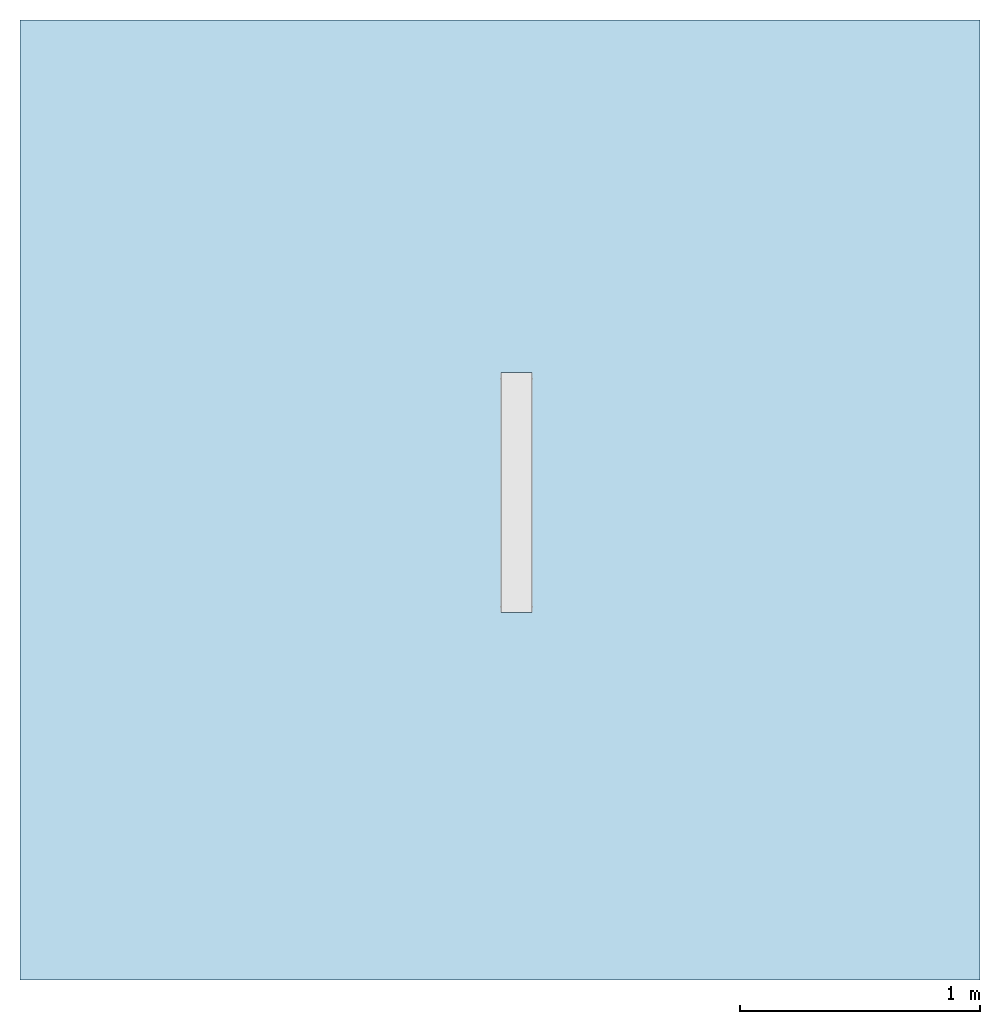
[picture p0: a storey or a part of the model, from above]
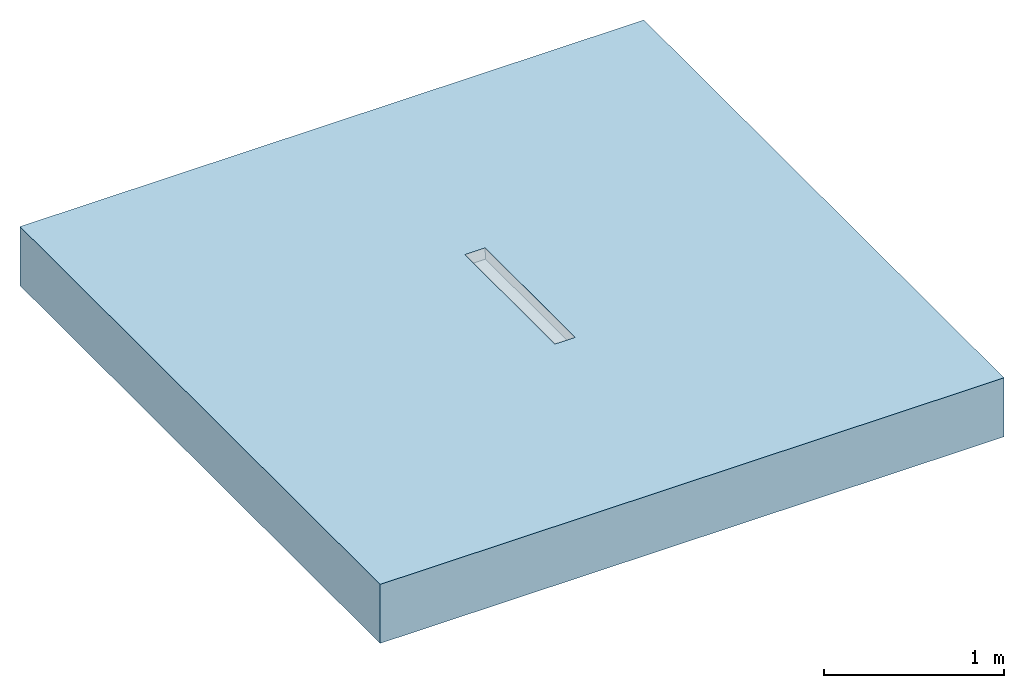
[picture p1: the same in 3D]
Properties of the parts of a building model (IFC2X3)

# File
Description: ViewDefinition [CoordinationView]
File name: Project Number
Time: 2014-06-06T14:47:46
Written by: The EXPRESS Data Manager Version 5.01.0100.02.64mod : 6 Jun 2012
Made in: 20130308_1515(x64) - Exporter 2014.0.2013.0308 - Default UI
Comment: STEP Physical File produced by: The EXPRESS Data Manager Version 5.01.0100.02.64mod : 6 Jun 2012 * Module: EDMstepFileFactory/EDMstandAlone * Creation date: Fri Jun 06 14:47:46 2014 * Host: IN-BLR-PC-0010 * Database: C:\Users\palleri\AppData\Local\Temp\{3695704A-249B-45A1-9260-636B70878DE3}\ifc * Database version: 5507 * Database creation date: Fri Jun 06 14:47:45 2014 * Schema: IFC2X3 * Model: DataRepository.ifc * Model creation date: Fri Jun 06 14:47:45 2014 * Header model: DataRepository.ifc_HeaderModel * Header model creation date: Fri Jun 06 14:47:45 2014 * EDMuser: sdai-user * EDMgroup: sdai-group * License ID and type: 5605 : Permanent license. Expiry date: * EDMstepFileFactory options: 020000

# IfcProject, Project Number
LongName: Project Name; Phase: Project Status

# IfcSite, Default
RefLatitude: 42, 21, 30, 344238; RefLongitude: -71, -3, -35, -194702; RefElevation: 0 mm

# IfcBuilding
Pset_BuildingCommon - NumberOfStoreys: 1
Other - Project Status: Project Status; Client Name: Owner; Project Address: ## Street City, State Zip; Project Name: Project Name; Project Issue Date: Issue Date; Project Number: Project Number

# IfcBuildingStorey, Level 1
LongName: Level 1; Elevation: 0 mm
Constraints - Elevation Base: Project Base Point; Elevation: 0 mm
Graphics - Symbol at End 1 Default: no; Line Weight: 1; Symbol: M_Level Head - Circle: M_Level Head - Circle; Symbol at End 2 Default: yes; Color: 0; Line Pattern: Center
Identity Data - Building Story: yes; Structural: no; Name: Level 1
Dimensions - Computation Height: 0 mm

# IfcFlowTerminal: 36943 - Adjustable Channel - Shallow Section - 1000mm LG - Invert Depth 55/77mm, ACO Freedeck Adjustable Height Channel Shallow Section Stainless Steel:36943 - Adjustable Channel - Shallow Section - 1000mm LG - Invert Depth 55/77mm:317948
In: Level 1
Material: Stainless Steel Grade 304
Dimensions - Height @ Invert 1 (55 -77mm): 77 mm; Height @ Invert 2 (55 -77mm): 77 mm; Channel End Length: -1000 mm; Grating End Length: 1000 mm
Other - Height @ Invert 2 Min & Max: 77 mm; Height @ Invert 1 Min & Max: 77 mm; Top Piece Void Height @ Invert 1: 31 mm; Top Piece Void Height @ Invert 2: 31 mm; Nos: 32
Construction - End Plate Invert 2: no; 36954 - Grating - Plain Mesh - Stainless Steel 304 - 500mm long: no; End Plate Invert 1: no; 00272 - Grating - Slotted Grating - Stainless Steel 304 - 1000mm long: no; 36955 - Grating - Plain Mesh - Stainless Steel 304 - 1000mm long: yes; 00273 - Grating - Slotted Grating - Stainless Steel 304 - 500mm long: no
Phasing - Phase Created: New Construction
Constraints - Moves With Nearby Elements: no; Level: Level: Level 1
Identity Data - Mark: 29; E-mail Sales: abdcommercial@aco.co.uk; Watermarked With: BIM Manager Premium Suite; Watermarked By: www.acobd.com; Watermark1: This file is the property of ACO Technologies PLC; Watermark2: This file is water marked and users are prohibited to reproduce, adapt, distribute this information; E-mail Technical: abdtechnical@aco.co.uk; Website: www.acobd.com; Address: ACO Business Centre, Caxton Road, Bedford, MK41 0LF; Fax: +44 (0)1462 851490; Manufacturer: ACO Building Drainage; Telephone: +44 (0)1462 816666
Pset_ManufacturerTypeInformation - Manufacturer: ACO Building Drainage
Model Properties - Grating Product Code 36954: Load Class A15 - Mesh Grating - 14mm x 30mm Mesh - Stainless Steel 304 - 500mm long - 1.6kg; Grating Product Code 36955: Load Class A15 - Mesh Grating - 14mm x 30mm Mesh - Stainless Steel 304 - 1000mm long - 3.0kg; Grating Product Code 00273: Load Class A15 - Slotted Grating - 10 x 80mm Slot - Stainless Steel 304 - 500mm long - 1.0kg; Grating Product Code 00272: Load Class A15 - Slotted Grating - 10 x 80mm Slot - Stainless Steel 304 - 1000mm long - 2.2kg; End Plate Product Code 36951: End Plate - Stainless Steel 304 for Invert Depth - 55/77mm - 0.1Kg
General - Product Type: Linear Deck Drainage System; Price: POA - contact ACO; Channel Recycled Material Content: 60-70%; Weight (Kg): 4.9kg; Product Code: 36943; NBS Specification: NBS Section R10 Gravity Rainwater Drainage Systems, Subsection 365; Product Range: ACO Freedeck; Dimensions (LxWxH): 1000 x 130 x 55/77; Product Standard: BS EN 1433:2002, CE marked; Channel Colour: Mid Grey; Maintenance Guidelines: X:\Electronic Literature\ABD Electronic Literature\Roof and Balcony Drainage\ACO Freedeck Brochure.pdf; Channel Material: Stainless Steel Grade 304; Product Description: ACO Freedeck Adjustable Channel - Shallow Section; Channel Recyclable: Fully recyclable; Load Class: A15; Installation Guidelines: X:\Electronic Literature\ABD Electronic Literature\Roof and Balcony Drainage\ACO Freedeck Brochure.pdf
Materials and Finishes - Material: Stainless Steel Grade 304

# IfcOpeningElement: Recess
In: Level 1
Constraints - Related to Mass: no; Height Offset From Level: 0 mm; Room Bounding: yes; Level: Level: Level 1
Phasing - Phase Created: New Construction
Dimensions - Thickness: 400 mm; Area: 16 m2; Volume: 6.38981 m3; Perimeter: 16000 mm
Structural - Enable Analytical Model: no; Structural: no
Analytical Properties - Roughness: 1; Heat Transfer Coefficient (U): 2.615; Thermal Resistance (R): 0.382409; Thermal mass: 604440; Absorptance: 0.1
Construction - Function: Interior; Default Thickness: 400 mm
Graphics - Coarse Scale Fill Color: 0
Materials and Finishes - Structural Material: Concrete, Broom Finish

# IfcSlab: Floor:Generic Floor - 400mm, Floor:Generic Floor - 400mm:193825
In: Level 1
PredefinedType: FLOOR; Material: Concrete, Broom Finish 400 mm
Constraints - Related to Mass: no; Height Offset From Level: 0 mm; Room Bounding: yes; Level: Level: Level 1
Phasing - Phase Created: New Construction
Dimensions - Thickness: 400 mm; Area: 16 m2; Volume: 6.38981 m3; Perimeter: 16000 mm
Structural - Enable Analytical Model: no; Structural: no
Pset_SlabCommon - Reference: Generic Floor - 400mm; IsExternal: no; LoadBearing: yes; ThermalTransmittance: 2.615 kg/K/s3
Analytical Properties - Roughness: 1; Heat Transfer Coefficient (U): 2.615; Thermal Resistance (R): 0.382409; Thermal mass: 604440; Absorptance: 0.1
Construction - Function: Interior; Default Thickness: 400 mm
Graphics - Coarse Scale Fill Color: 0
Materials and Finishes - Structural Material: Concrete, Broom Finish
